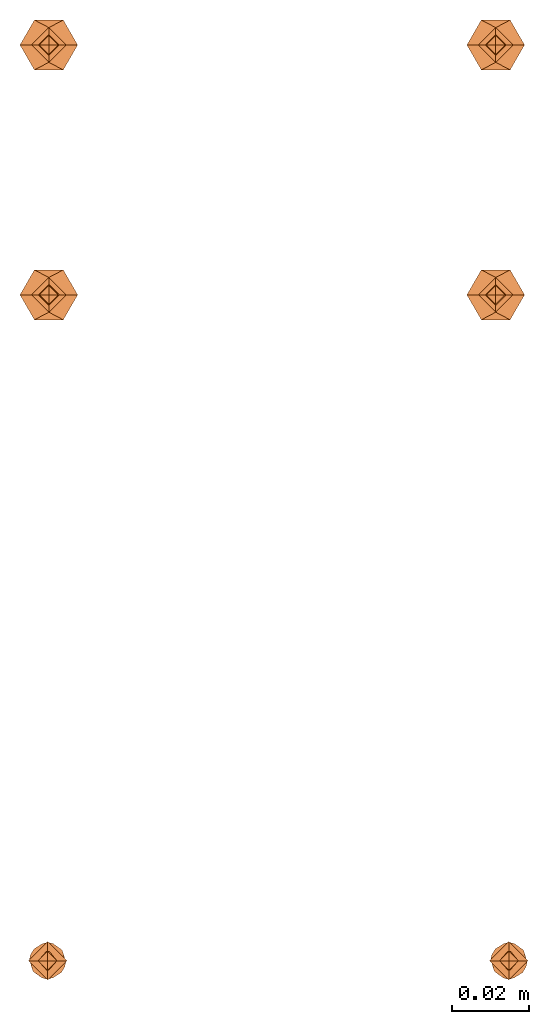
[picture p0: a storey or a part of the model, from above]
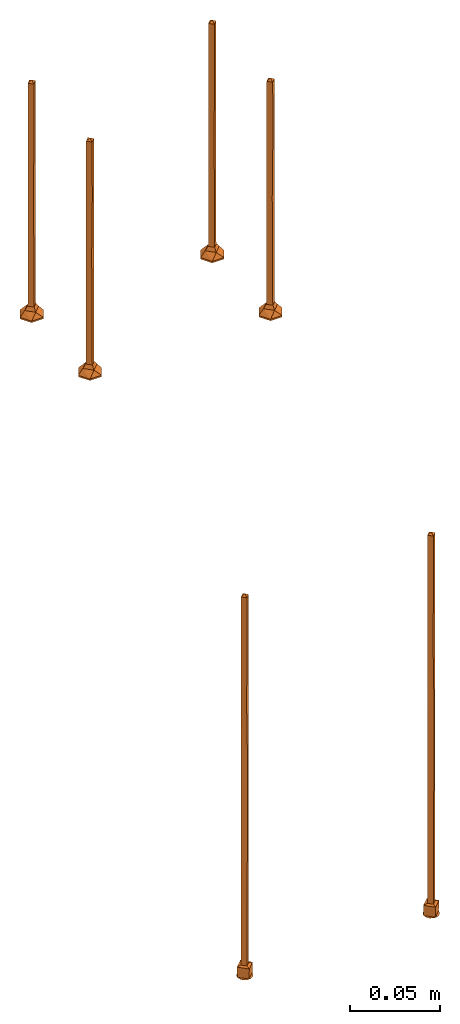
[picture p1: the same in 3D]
Properties of the parts of a building model (IFC2X3)

# File
Description: ViewDefinition [CoordinationView_V2.0], RevitIdentifiers [VersionGUID: 24bfaa4f-541c-4f90-8074-342e95d23307, NumberOfSaves: 58], CoordinateReference [CoordinateBase: Shared Coordinates, ProjectSite: Internal]
File name: Project Number
Time: 2025-12-12T10:21:45+07:00
Written by: ODA SDAI 24.6
Made in: Autodesk Revit 24.2.10.64 (ENG) - IFC 24.2.10.64

# IfcProject, Project Number
LongName: Project Name; Phase: Project Status

# IfcSite, Default
RefLatitude: 42, 21, 31, 401672; RefLongitude: -71, -3, -24, -345703; RefElevation: 0 mm

# IfcBuilding, Building Name
LongName: Building Name
Pset_BuildingCommon - NumberOfStoreys: 3

# IfcBuildingStorey: Level:ISL_Level Name & Elevation - End 2 - Project (15)
In: Building Name
Pset_AirSideSystemInformation - sets with these values: 2
Name | LongName = Name | Elevation (mm)
u/s GRADEBEAM | u/s GRADEBEAM | 8950
MAIN FLOOR | MAIN FLOOR | 10000
T/O STAGE | T/O STAGE | 11200
U/S DAYCARE ROOF | U/S DAYCARE ROOF | 13448
U/S SECOND FLOOR | U/S SECOND FLOOR | 13893
MEZZANINE | MEZZANINE | 14000
SECOND FLOOR | SECOND FLOOR | 14100
DAYCARE PARAPET | DAYCARE PARAPET | 14900
LOWER PARAPET | LOWER PARAPET | 15400
U/S THIRD FLOOR | U/S THIRD FLOOR | 17993
THIRD FLOOR | THIRD FLOOR | 18200
U/S GYM DECK | U/S GYM DECK | 18500
THIRD FLOOR PARAPET | THIRD FLOOR PARAPET | 19200
u/s ROOF DECK | u/s ROOF DECK | 22300
HIGHER PARAPET | HIGHER PARAPET | 23100

# IfcBeam: ISL_Heavy Timber:265x532 (2)
In: U/S SECOND FLOOR
Type - Pset_BeamCommon - IsExternal: no; LoadBearing: yes
Classification: B10 Uniformat (Uniformat); Material: Wood - GLULAM
Pset_BeamCommon - Reference: 265x532; Slope: 0 deg
Pset_QuantityTakeOff - Reference: 265x532; sets with these values: 2
Name (ISL_Heavy Timber:265x532:...) | Span (mm)
2235925 | 1005
2246596 | 238.75

# IfcBuildingElementProxy: CSK SCREW 8mm_with_Void:8-160/143_90° (4)
In: T/O STAGE
Type - Material: <Unnamed>
Pset_BuildingElementProxyCommon - Reference: 8-160/143_90°; sets with these values: 2
Name (CSK SCREW 8mm_with_Void:8-160/143_90°:...)
2241689
2241698
2241707
2241732

# IfcBuildingElementProxy: CSK SCREW 8mm_with_Void:8-260/243_90° (2)
Type - Material: <Unnamed>
Pset_BuildingElementProxyCommon - Reference: 8-260/243_90°; sets with these values: 2
Name (CSK SCREW 8mm_with_Void:8-260/243_90°:...) | In
2429648 | U/S SECOND FLOOR
2429788 | U/S DAYCARE ROOF

# IfcBuildingElementProxy: CYL SCREW 8mm:8-260/244 (2)
In: T/O STAGE
Type - Material: <Unnamed>
Pset_BuildingElementProxyCommon - Reference: 8-260/244; sets with these values: 2
Name (CYL SCREW 8mm:8-260/244:...)
2235927
2302071

# IfcBuildingElementProxy: Structural Connections 1:Structural Connections 1, Structural Connections 1:Structural Connections 1:2240805
In: U/S DAYCARE ROOF
Type - Material: Metal - Steel - 345 MPa
Pset_BuildingElementProxyCommon - Reference: Structural Connections 1; sets with these values: 2

# IfcBuildingElementProxy: Structural Connections 3:Structural Connections 3, Structural Connections 3:Structural Connections 3:2240819
In: U/S DAYCARE ROOF
Type - Material: Metal - Steel - 345 MPa
Pset_BuildingElementProxyCommon - Reference: Structural Connections 3; sets with these values: 2

# IfcBuildingElementProxy: Structural Connections 54:Structural Connections 1, Structural Connections 54:Structural Connections 1:2240834
In: U/S DAYCARE ROOF
Type - Material: Metal - Steel - 345 MPa
Pset_BuildingElementProxyCommon - Reference: Structural Connections 1; sets with these values: 2

# IfcWallStandardCase: Basic Wall:200 CONCRETE, Basic Wall:200 CONCRETE:2236193
In: U/S SECOND FLOOR
Type - PredefinedType: STANDARD; Material: Concrete - Cast-in-Place Concrete 200 mm
Type - Pset_WallCommon - IsExternal: yes
Pset_QuantityTakeOff - Reference: 200 CONCRETE; sets with these values: 2
Pset_WallCommon - LoadBearing: yes; Reference: 200 CONCRETE; ExtendToStructure: no
